One B-rep face of a CAD part: STEP entity #588.
In plain terms, the planar face has unit normal (1, 0, 0).
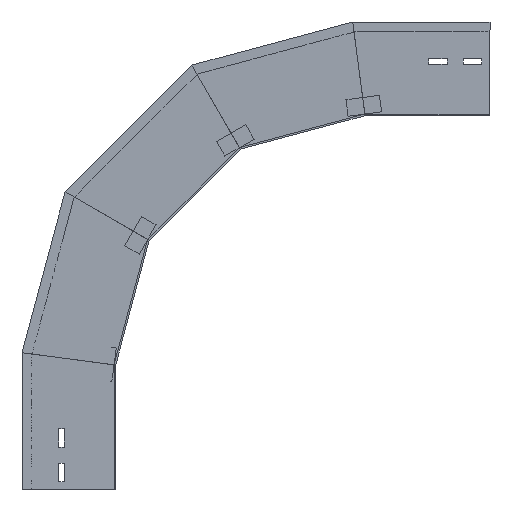
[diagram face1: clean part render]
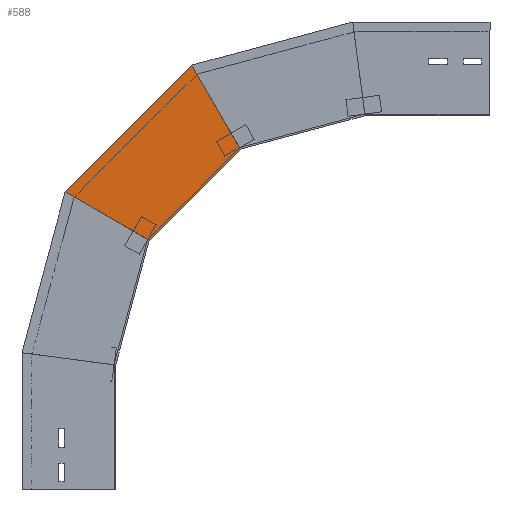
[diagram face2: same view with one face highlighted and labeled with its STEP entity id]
Its self-contained STEP definition (entity closure, numbers rounded to 3 decimals):
#51 = LINE ( 'NONE', #974, #221 ) ;
#59 = ORIENTED_EDGE ( 'NONE', *, *, #840, .F. ) ;
#68 = EDGE_LOOP ( 'NONE', ( #1561, #1551, #59, #198 ) ) ;
#70 = VECTOR ( 'NONE', #202, 1000. ) ;
#95 = DIRECTION ( 'NONE',  ( 0., 0., -1. ) ) ;
#193 = VECTOR ( 'NONE', #1186, 1000. ) ;
#198 = ORIENTED_EDGE ( 'NONE', *, *, #1117, .F. ) ;
#202 = DIRECTION ( 'NONE',  ( 0., -0.707, 0.707 ) ) ;
#221 = VECTOR ( 'NONE', #1536, 1000. ) ;
#268 = CARTESIAN_POINT ( 'NONE',  ( 0., 62.95, 355.751 ) ) ;
#276 = VERTEX_POINT ( 'NONE', #707 ) ;
#395 = DIRECTION ( 'NONE',  ( 1., 0., 0. ) ) ;
#411 = PLANE ( 'NONE',  #1422 ) ;
#426 = LINE ( 'NONE', #268, #193 ) ;
#520 = EDGE_CURVE ( 'NONE', #838, #854, #51, .T. ) ;
#556 = CARTESIAN_POINT ( 'NONE',  ( 0., -16.599, 276.201 ) ) ;
#588 = ADVANCED_FACE ( 'NONE', ( #980 ), #411, .T. ) ;
#707 = CARTESIAN_POINT ( 'NONE',  ( 0., 60.748, 357.953 ) ) ;
#838 = VERTEX_POINT ( 'NONE', #1791 ) ;
#840 = EDGE_CURVE ( 'NONE', #958, #854, #1809, .T. ) ;
#854 = VERTEX_POINT ( 'NONE', #1090 ) ;
#930 = CARTESIAN_POINT ( 'NONE',  ( 0., -16.599, 276.201 ) ) ;
#958 = VERTEX_POINT ( 'NONE', #1168 ) ;
#974 = CARTESIAN_POINT ( 'NONE',  ( 0., -174.081, 367.123 ) ) ;
#980 = FACE_OUTER_BOUND ( 'NONE', #68, .T. ) ;
#997 = VECTOR ( 'NONE', #1767, 1000. ) ;
#1090 = CARTESIAN_POINT ( 'NONE',  ( 0., -149.719, 409.32 ) ) ;
#1117 = EDGE_CURVE ( 'NONE', #276, #958, #1501, .T. ) ;
#1168 = CARTESIAN_POINT ( 'NONE',  ( 0., -40.117, 299.719 ) ) ;
#1186 = DIRECTION ( 'NONE',  ( 0., -0.707, 0.707 ) ) ;
#1398 = EDGE_CURVE ( 'NONE', #276, #838, #426, .T. ) ;
#1422 = AXIS2_PLACEMENT_3D ( 'NONE', #556, #395, #95 ) ;
#1501 = LINE ( 'NONE', #1806, #997 ) ;
#1536 = DIRECTION ( 'NONE',  ( 0., -0.5, -0.866 ) ) ;
#1551 = ORIENTED_EDGE ( 'NONE', *, *, #520, .T. ) ;
#1561 = ORIENTED_EDGE ( 'NONE', *, *, #1398, .T. ) ;
#1767 = DIRECTION ( 'NONE',  ( 0., -0.866, -0.5 ) ) ;
#1791 = CARTESIAN_POINT ( 'NONE',  ( 0., -91.484, 510.185 ) ) ;
#1806 = CARTESIAN_POINT ( 'NONE',  ( 0., -78.533, 277.539 ) ) ;
#1809 = LINE ( 'NONE', #930, #70 ) ;
